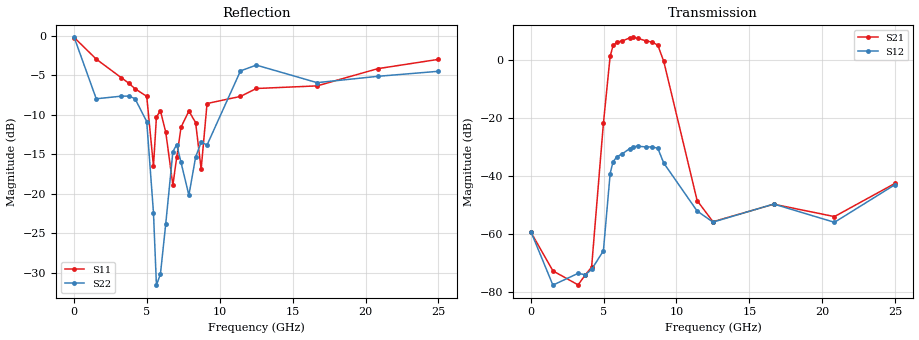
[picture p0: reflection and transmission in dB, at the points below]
!Agilent Technologies,E8364B,MY43040894,A.07.50.67
!Agilent E8364B: A.07.50.67
!Date: Wednesday, July 07, 2021 13:14:33
!Correction: S11(Full 2 Port(1,2))
!S21(Full 2 Port(1,2))
!S12(Full 2 Port(1,2))
!S22(Full 2 Port(1,2))
!S2P File: Measurements: S11, S21, S12, S22:
# Hz S  dB  R 50
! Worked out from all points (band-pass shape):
!   8001 points, 10 MHz to 25 GHz, reference 50 ohm
!   highest |S21| = 7.66 dB at 7.042 GHz (marker M1); lowest = -77.7 dB at 3.252 GHz (marker M2)
!   |S21| within 3 dB of the highest: 5.633 GHz to 8.759 GHz (3.126 GHz wide, 43.4 % of centre)
!   lowest |S11| = -18.9 dB at 6.779 GHz (marker M3), VSWR 1.26, Z = 62.1 + j3.87 ohm
!   |S11| at or under -10 dB: 5.137 GHz to 5.671 GHz (533.7 MHz wide, 9.87 % of centre); 6.017 GHz to 7.675 GHz (1.657 GHz wide, 24.2 % of centre); 8.225 GHz to 9.007 GHz (782.4 MHz wide, 9.08 % of centre)
!   |S22| runs from -33.0 to -0.2 dB; largest |S21 - S12| = 2.4
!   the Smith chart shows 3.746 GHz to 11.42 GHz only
!   S11 on the Smith chart (normalised r, x): 3.746 GHz: 0.47, +0.59; 4.986 GHz: 1.75, -0.93; 5.926 GHz: 0.51, -0.15; 7.338 GHz: 0.67, -0.30; 9.125 GHz: 0.50, +0.28; 11.42 GHz: 2.36, -0.28
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1e7  -0.25 -4.8  -59.48 -109.7  -59.29 17.4  -0.23 -8.0
1.521895e9  -2.98 -137.0  -72.84 63.0  -77.76 -163.8  -8.00 -92.7
3.252452e9  -5.35 137.0  -77.69 -18.2  -73.69 -82.3  -7.67 -152.0
3.746005e9  -6.02 110.0  -74.20 -121.2  -74.21 18.2  -7.67 -172.2
4.177082e9  -6.72 80.0  -71.55 130.7  -72.36 -131.3  -7.97 166.8
4.986134e9  -7.70 -32.5  -21.97 157.6  -65.91 61.4  -10.89 108.8
5.448449e9  -16.54 -70.7  1.10 -20.7  -39.29 -93.4  -22.42 26.8
5.651492e9  -10.30 -98.3  4.87 -103.1  -35.16 -174.0  -31.59 -137.0
5.926382e9  -9.53 -157.5  6.06 164.8  -33.46 95.5  -30.18 94.3
6.291861e9  -12.24 144.5  6.47 72.7  -32.46 5.8  -23.81 -91.0
6.779166e9  -18.92 15.8  7.44 -33.3  -30.72 -96.0  -14.71 -157.3
7.041561e9  -15.43 -71.8  7.66 -89.0  -30.03 -149.9  -13.79 163.0
7.338318e9  -11.60 -126.7  7.35 -149.7  -29.83 150.4  -16.06 109.1
7.878726e9  -9.55 170.5  6.51 106.4  -30.12 48.7  -20.21 -59.3
8.341041e9  -11.03 126.9  6.01 14.4  -30.11 -40.1  -15.37 -147.9
8.719015e9  -16.91 152.6  4.96 -74.7  -30.58 -126.6  -13.50 148.2
9.125102e9  -8.60 140.6  -0.60 -176.5  -35.66 133.0  -13.85 52.5
1.141794e10  -7.70 -7.0  -48.62 -144.1  -52.22 -140.3  -4.47 -138.5
1.2505e10  -6.70 -49.8  -55.90 34.3  -56.03 40.2  -3.74 172.6
1.667208e10  -6.37 -170.8  -49.86 -75.9  -49.80 -81.1  -5.96 20.1
2.083604e10  -4.19 27.3  -54.13 -79.6  -56.11 -80.2  -5.16 -64.4
2.5e10  -3.01 -87.0  -42.66 -81.1  -43.09 -77.4  -4.52 -117.5
